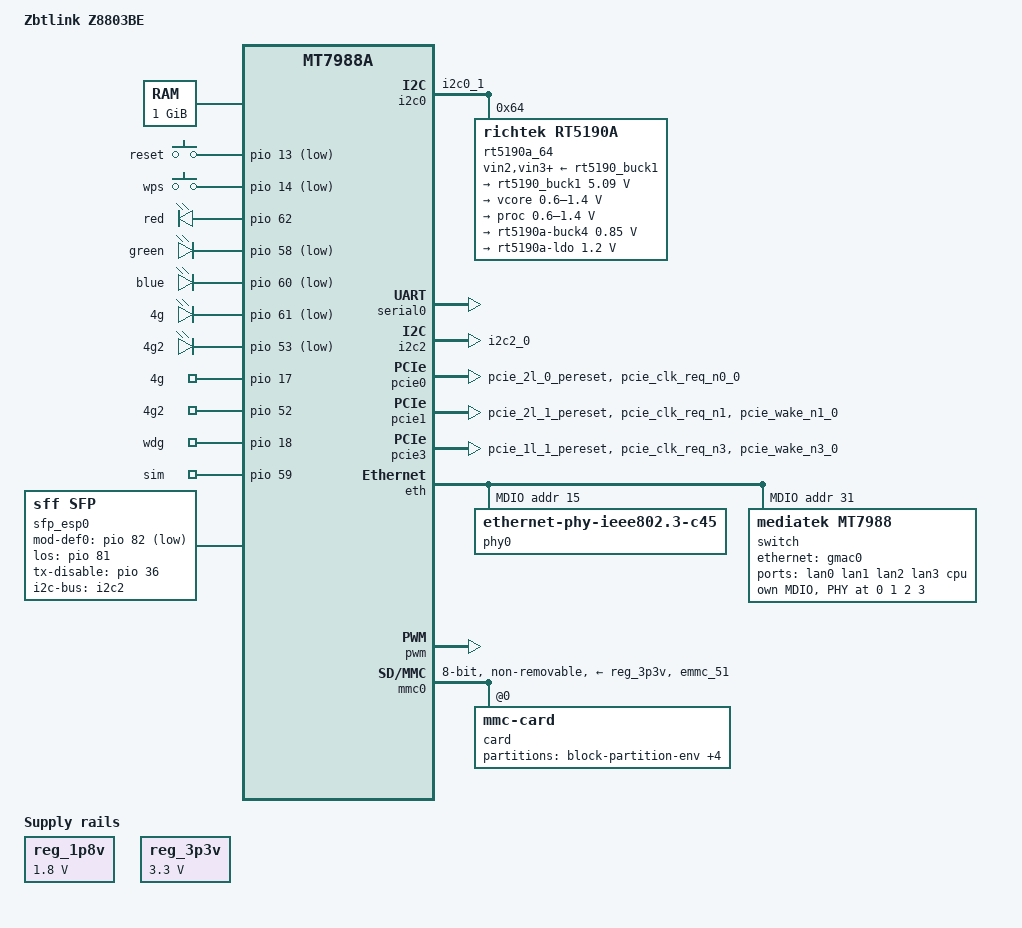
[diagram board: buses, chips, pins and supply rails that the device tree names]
// SPDX-License-Identifier: (GPL-2.0 OR MIT)
/*
 * Draft modifications for OpenRouterLab / ZBT Z8803BE eMMC:
 * - RAM fixed from 256 MiB placeholder to 1 GiB.
 * - rootdisk points to rootfs_partition.
 * - eMMC block-device partnames added: u-boot-env, factory, fip, kernel, rootfs.
 * - Generic zbtlink,zbt-z8803be compatible added after eMMC-compatible.
 * - Undefined phy_calibration_p0..p3 references are commented out until vendor
 *   provides the missing factory/NVMEM definitions.
 *
 * This is a compile-only draft. Do not flash a firmware built from this file yet.
 */

/*
 * Copyright (C) 2021 MediaTek Inc.
 * Author: Sam.Shih <sam.shih@mediatek.com>
 */

/dts-v1/;
#include <dt-bindings/input/input.h>
#include <dt-bindings/gpio/gpio.h>
#include "mt7988.dtsi"

/ {
	model = "Zbtlink Z8803BE";
	compatible = "zbtlink,zbt-z8803be,mt7988a-emmc",
		     "zbtlink,zbt-z8803be", "mediatek,mt7988a";

	chosen {
		bootargs = "console=ttyS0,115200n1 loglevel=8  \
			    earlycon=uart8250,mmio32,0x11000000 \
			    root=PARTLABEL=rootfs rootwait \
			    rootfstype=squashfs,f2fs pci=pcie_bus_perf";
		rootdisk = <&rootfs_partition>;
	};

	memory {
		device_type = "memory";
		reg = <0x00 0x40000000 0x00 0x40000000>;
	};

	gpio-keys {
		compatible = "gpio-keys";

		reset {
			label = "reset";
			linux,code = <KEY_RESTART>;
			gpios = <&pio 13 GPIO_ACTIVE_LOW>;
		};

		wps {
			label = "wps";
			linux,code = <KEY_WPS_BUTTON>;
			gpios = <&pio 14 GPIO_ACTIVE_LOW>;
		};
	};

	gpio-leds {
		compatible = "gpio-leds";

		red {
			label = "red";
			gpios = <&pio 62 GPIO_ACTIVE_HIGH>;
			default-state = "on";
		};

		green {
			label = "green";
			gpios = <&pio 58 GPIO_ACTIVE_LOW>;
			default-state = "off";
		};

		blue {
			label = "blue";
			gpios = <&pio 60 GPIO_ACTIVE_LOW>;
			default-state = "off";
		};

		4g {
			label = "4g";
			gpios = <&pio 61 GPIO_ACTIVE_LOW>;
			default-state = "off";
		};

		4g2 {
			label = "4g2";
			gpios = <&pio 53 GPIO_ACTIVE_LOW>;
			default-state = "off";
		};
	};

	gpio-export {
		compatible = "gpio-export";
		#size-cells = <0>;
			
		4g {
				gpio-export,name = "4g";
				gpio-export,output = <0>;
				gpios = <&pio 17 GPIO_ACTIVE_HIGH>;
		};
		4g2 {
				gpio-export,name = "4g2";
				gpio-export,output = <0>;
				gpios = <&pio 52 GPIO_ACTIVE_HIGH>;
		};
		wdg {
				gpio-export,name = "wdg";
				gpio-export,output = <0>;
				gpios = <&pio 18 GPIO_ACTIVE_HIGH>;
		};
		sim {
				gpio-export,name = "sim";
				gpio-export,output = <1>;
				gpios = <&pio 59 GPIO_ACTIVE_HIGH>;
		};
    };

	wsys_adie: wsys_adie@0 {
	// fpga cases need to manual change adie_id / sku_type for dvt only
		compatible = "mediatek,rebb-mt7988-adie";
		adie_id = <7976>;
		sku_type = <3000>;
	};

	sfp_esp0: sfp@0 {
		compatible = "sff,sfp";
		i2c-bus = <&i2c2>;
		mod-def0-gpios = <&pio 82 1>;
		los-gpios = <&pio 81 0>;
		tx-disable-gpios = <&pio 36 0>;
		maximum-power-milliwatt = <3000>;
	};

	reg_1p8v: regulator-1p8v {
		compatible = "regulator-fixed";
		regulator-name = "fixed-1.8V";
		regulator-min-microvolt = <1800000>;
		regulator-max-microvolt = <1800000>;
		regulator-boot-on;
		regulator-always-on;
	};

	reg_3p3v: regulator-3p3v {
		compatible = "regulator-fixed";
		regulator-name = "fixed-3.3V";
		regulator-min-microvolt = <3300000>;
		regulator-max-microvolt = <3300000>;
		regulator-boot-on;
		regulator-always-on;
	};
};

&i2c0 {
	pinctrl-names = "default";
	pinctrl-0 = <&i2c0_pins>;
	status = "okay";

	rt5190a_64: rt5190a@64 {
		compatible = "richtek,rt5190a";
		reg = <0x64>;
		/*interrupts-extended = <&gpio26 0 IRQ_TYPE_LEVEL_LOW>;*/
		vin2-supply = <&rt5190_buck1>;
		vin3-supply = <&rt5190_buck1>;
		vin4-supply = <&rt5190_buck1>;

		regulators {
			rt5190_buck1: buck1 {
				regulator-name = "rt5190a-buck1";
				regulator-min-microvolt = <5090000>;
				regulator-max-microvolt = <5090000>;
				/* TODO: vendor DTS uses RT5190A_OPMODE_* macros without the matching dt-bindings header.

				 * Removed for compile-only validation.

				 * regulator-allowed-modes = <RT5190A_OPMODE_AUTO RT5190A_OPMODE_FPWM>;

				 */
				regulator-boot-on;
			};
			buck2 {
				regulator-name = "vcore";
				regulator-min-microvolt = <600000>;
				regulator-max-microvolt = <1400000>;
				regulator-boot-on;
			};
			buck3 {
				regulator-name = "proc";
				regulator-min-microvolt = <600000>;
				regulator-max-microvolt = <1400000>;
				regulator-boot-on;
			};
			buck4 {
				regulator-name = "rt5190a-buck4";
				regulator-min-microvolt = <850000>;
				regulator-max-microvolt = <850000>;
				/* TODO: vendor DTS uses RT5190A_OPMODE_* macros without the matching dt-bindings header.

				 * Removed for compile-only validation.

				 * regulator-allowed-modes = <RT5190A_OPMODE_AUTO RT5190A_OPMODE_FPWM>;

				 */
				regulator-boot-on;
			};
			ldo {
				regulator-name = "rt5190a-ldo";
				regulator-min-microvolt = <1200000>;
				regulator-max-microvolt = <1200000>;
				regulator-boot-on;
			};
		};
	};
};

&serial0 {
	status = "okay";
};

&i2c2 {
	pinctrl-names = "default";
	pinctrl-0 = <&i2c2_pins>;
	status = "okay";
};

&spi1 {
	pinctrl-names = "default";
	/* pin shared with snfi */
	pinctrl-0 = <&spic_pins>;
	status = "disabled";
};

&pcie0 {
	pinctrl-names = "default";
	pinctrl-0 = <&pcie0_pins>;
	wifi-reset-gpios = <&pio 7 GPIO_ACTIVE_HIGH>;
	wifi-reset-msleep = <100>;
	status = "okay";
};

&pcie1 {
	pinctrl-names = "default";
	pinctrl-0 = <&pcie1_pins>;
	status = "okay";
};

&pcie2 {
	pinctrl-names = "default";
	pinctrl-0 = <&pcie2_pins>;
	status = "disabled";
};

&pcie3 {
	pinctrl-names = "default";
	pinctrl-0 = <&pcie3_pins>;
	status = "okay";
};

&pio {
	gbe0_led0_pins: gbe0-pins {
		mux {
			function = "led";
			groups = "gbe0_led0";
		};
	};

	gbe1_led0_pins: gbe1-pins {
		mux {
			function = "led";
			groups = "gbe1_led0";
		};
	};

	gbe2_led0_pins: gbe2-pins {
		mux {
			function = "led";
			groups = "gbe2_led0";
		};
	};

	gbe3_led0_pins: gbe3-pins {
		mux {
			function = "led";
			groups = "gbe3_led0";
		};
	};

	i2p5gbe_led0_pins: 2p5gbe-pins {
		mux {
			function = "led";
			groups = "2p5gbe_led0";
		};
	};

	i2c0_pins: i2c0-pins-g0 {
		mux {
			function = "i2c";
			groups = "i2c0_1";
		};
	};

	i2c2_pins: i2c2-pins-g0 {
		mux {
			function = "i2c";
			groups = "i2c2_0";
		};

		conf {
			groups = "i2c2_0";
			drive-strength = <MTK_DRIVE_8mA>;
		};
	};

	pcie0_pins: pcie0-pins {
		mux {
			function = "pcie";
			groups = "pcie_2l_0_pereset", "pcie_clk_req_n0_0";
		};
	};

	pcie1_pins: pcie1-pins {
		mux {
			function = "pcie";
			groups = "pcie_2l_1_pereset", "pcie_clk_req_n1",
				 "pcie_wake_n1_0";
		};
	};

	pcie2_pins: pcie2-pins {
		mux {
			function = "pcie";
			groups = "pcie_1l_0_pereset", "pcie_clk_req_n2_0",
				 "pcie_wake_n2_0";
		};
	};

	pcie3_pins: pcie3-pins {
		mux {
			function = "pcie";
			groups = "pcie_1l_1_pereset", "pcie_clk_req_n3",
				 "pcie_wake_n3_0";
		};
	};

	spic_pins: spi1-pins {
		mux {
			function = "spi";
			groups = "spi1";
		};
	};

	pwm0_pin: pwm0-pin {
		mux {
			function = "pwm";
			groups = "pwm0";
		};
	};

	mmc0_pins_default: mmc0-pins-default {
		mux {
			function = "flash";
			groups = "emmc_51";
		};
	};

	mmc0_pins_uhs: mmc0-pins-uhs {
		mux {
			function = "flash";
			groups = "emmc_51";
		};
	};
};

&watchdog {
	status = "disabled";
};

&eth {
	status = "okay";

	gmac0: mac@0 {
		compatible = "mediatek,eth-mac";
		reg = <0>;
		//mtd-mac-address = <&factory 0xFFFF4>;
		mac-type = "xgdm";
		phy-mode = "10gbase-kr";

		fixed-link {
			speed = <10000>;
			full-duplex;
			pause;
		};
	};

	gmac1: mac@1 {
		compatible = "mediatek,eth-mac";
		reg = <1>;
		//mtd-mac-address = <&factory 0xFFFFA>;
		mac-type = "xgdm";
		phy-mode = "xgmii";
		phy-handle = <&phy0>;
	};

	gmac2: mac@2 {
		compatible = "mediatek,eth-mac";
		reg = <2>;
		//mtd-mac-address = <&factory 0xFFFEE>;
		mac-type = "xgdm";
		phy-mode = "10gbase-kr";
		managed = "in-band-status";
		sfp = <&sfp_esp0>;
	};

	mdio: mdio-bus {
		#address-cells = <1>;
		#size-cells = <0>;

		phy0: ethernet-phy@0 {
			pinctrl-names = "i2p5gbe-led";
			pinctrl-0 = <&i2p5gbe_led0_pins>;
			reg = <15>;
			compatible = "ethernet-phy-ieee802.3-c45";
			phy-mode = "xgmii";
		};
		switch@0 {
			compatible = "mediatek,mt7988";
			reg = <31>;
			ports {
				#address-cells = <1>;
				#size-cells = <0>;

				port@0 {
					reg = <0>;
					label = "lan0";
					phy-mode = "gmii";
					phy-handle = <&sphy0>;
				};

				port@1 {
					reg = <1>;
					label = "lan1";
					phy-mode = "gmii";
					phy-handle = <&sphy1>;
				};

				port@2 {
					reg = <2>;
					label = "lan2";
					phy-mode = "gmii";
					phy-handle = <&sphy2>;
				};

				port@3 {
					reg = <3>;
					label = "lan3";
					phy-mode = "gmii";
					phy-handle = <&sphy3>;
				};

				port@6 {
					reg = <6>;
					label = "cpu";
					ethernet = <&gmac0>;
					phy-mode = "10gbase-kr";

					fixed-link {
						speed = <10000>;
						full-duplex;
						pause;
					};
				};
			};

			mdio {
				compatible = "mediatek,dsa-slave-mdio";
				#address-cells = <1>;
				#size-cells = <0>;

				sphy0: switch_phy0@0 {
					compatible = "ethernet-phy-id03a2.9481";
					reg = <0>;
					pinctrl-names = "gbe-led";
					pinctrl-0 = <&gbe0_led0_pins>;
					/* TODO: vendor DTS references undefined phy_calibration_p0.
					 * Removed for compile-only draft until factory/NVMEM offsets are verified.
					 * nvmem-cells = <&phy_calibration_p0>;
					 * nvmem-cell-names = "phy-cal-data";
					 */
				};

				sphy1: switch_phy1@1 {
					compatible = "ethernet-phy-id03a2.9481";
					reg = <1>;
					pinctrl-names = "gbe-led";
					pinctrl-0 = <&gbe1_led0_pins>;
					/* TODO: vendor DTS references undefined phy_calibration_p1.
					 * Removed for compile-only draft until factory/NVMEM offsets are verified.
					 * nvmem-cells = <&phy_calibration_p1>;
					 * nvmem-cell-names = "phy-cal-data";
					 */
				};

				sphy2: switch_phy2@2 {
					compatible = "ethernet-phy-id03a2.9481";
					reg = <2>;
					pinctrl-names = "gbe-led";
					pinctrl-0 = <&gbe2_led0_pins>;
					/* TODO: vendor DTS references undefined phy_calibration_p2.
					 * Removed for compile-only draft until factory/NVMEM offsets are verified.
					 * nvmem-cells = <&phy_calibration_p2>;
					 * nvmem-cell-names = "phy-cal-data";
					 */
				};

				sphy3: switch_phy3@3 {
					compatible = "ethernet-phy-id03a2.9481";
					reg = <3>;
					pinctrl-names = "gbe-led";
					pinctrl-0 = <&gbe3_led0_pins>;
					/* TODO: vendor DTS references undefined phy_calibration_p3.
					 * Removed for compile-only draft until factory/NVMEM offsets are verified.
					 * nvmem-cells = <&phy_calibration_p3>;
					 * nvmem-cell-names = "phy-cal-data";
					 */
				};
			};
		};
	};
};

/* TODO compile-only: OpenWrt source tree used here does not expose label &hnat for this DTS.
 * &hnat {
 * 	mtketh-wan = "eth1";
 * 	mtketh-lan = "lan";
 * 	mtketh-lan2 = "eth2";
 * 	mtketh-max-gmac = <3>;
 * 	//mtketh-ppe-num = <3>;
 * 	status = "okay";
 * };
 */

/* TODO compile-only: OpenWrt source tree used here does not expose label &slot0; Wi-Fi PCIe child will be handled later after compile succeeds.
 * &slot0 {
 * 	mt7996@0,0 {
 * 		reg = <0x0000 0 0 0 0>;
 * 		device_type = "pci";
 * 		//mediatek,mtd-eeprom = <&factory 0x0>;
 * 	};
 * };
 */

&pwm {
	status = "okay";
};

&mmc0 {
	pinctrl-names = "default", "state_uhs";
	pinctrl-0 = <&mmc0_pins_default>;
	pinctrl-1 = <&mmc0_pins_uhs>;
	bus-width = <8>;
	max-frequency = <200000000>;
	cap-mmc-highspeed;
	mmc-hs200-1_8v;
	mmc-hs400-1_8v;
	hs400-ds-delay = <0x12814>;
	vqmmc-supply = <&reg_1p8v>;
	vmmc-supply = <&reg_3p3v>;
	non-removable;
	no-sd;
	no-sdio;
	status = "okay";


	card@0 {
		compatible = "mmc-card";
		reg = <0>;

		block {
			compatible = "block-device";

			partitions {
				block-partition-env {
					partname = "u-boot-env";

					nvmem-layout {
						compatible = "u-boot,env";
					};
				};

				block-partition-factory {
					partname = "factory";
				};

				block-partition-fip {
					partname = "fip";
				};

				block-partition-kernel {
					partname = "kernel";
				};

				rootfs_partition: block-partition-rootfs {
					partname = "rootfs";
				};
			};
		};
	};
};
